VERSION 5.7 ;
  NOWIREEXTENSIONATPIN ON ;
  DIVIDERCHAR "/" ;
  BUSBITCHARS "[]" ;
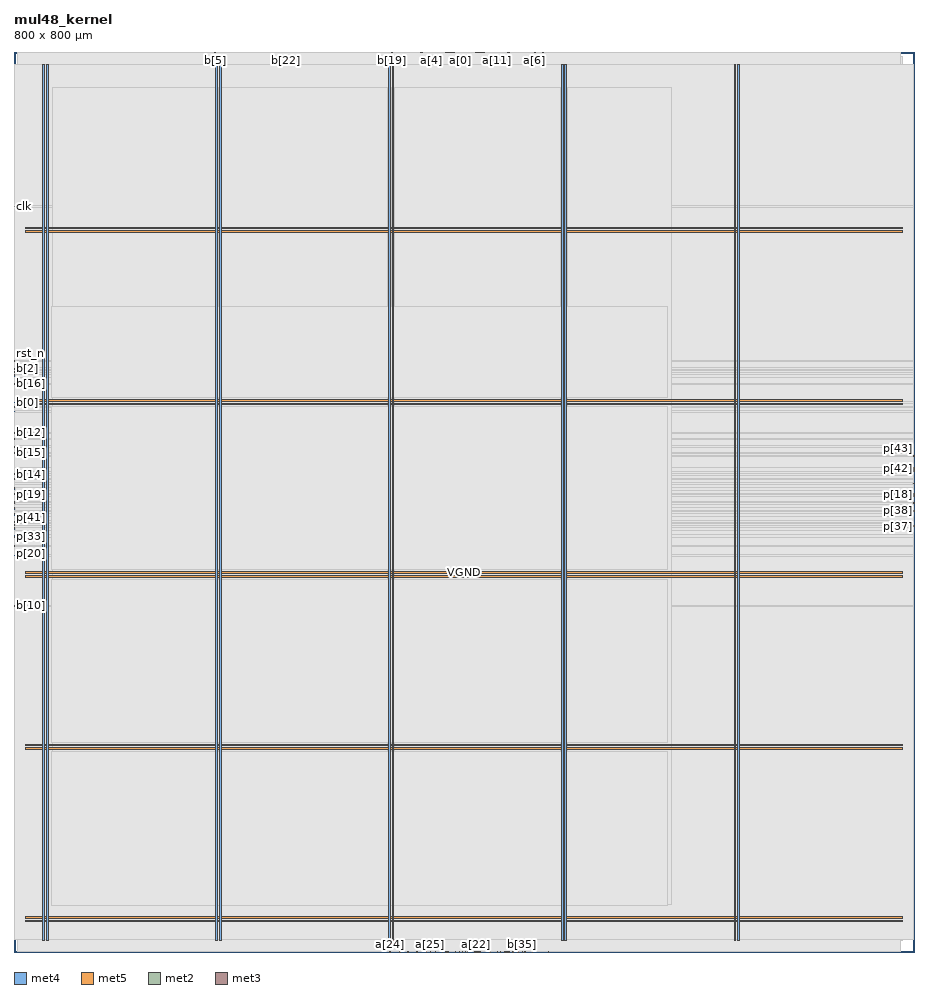
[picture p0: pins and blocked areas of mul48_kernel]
MACRO mul48_kernel
  CLASS BLOCK ;
  FOREIGN mul48_kernel ;
  ORIGIN 0.000 0.000 ;
  SIZE 800.000 BY 800.000 ;
  PIN VGND
    DIRECTION INOUT ;
    USE GROUND ;
    PORT
      LAYER met4 ;
        RECT 28.940 10.640 30.540 789.040 ;
    END
    PORT
      LAYER met4 ;
        RECT 182.540 10.640 184.140 789.040 ;
    END
    PORT
      LAYER met4 ;
        RECT 336.140 10.640 337.740 789.040 ;
    END
    PORT
      LAYER met4 ;
        RECT 489.740 10.640 491.340 789.040 ;
    END
    PORT
      LAYER met4 ;
        RECT 643.340 10.640 644.940 789.040 ;
    END
    PORT
      LAYER met5 ;
        RECT 10.120 30.030 789.820 31.630 ;
    END
    PORT
      LAYER met5 ;
        RECT 10.120 183.210 789.820 184.810 ;
    END
    PORT
      LAYER met5 ;
        RECT 10.120 336.390 789.820 337.990 ;
    END
    PORT
      LAYER met5 ;
        RECT 10.120 489.570 789.820 491.170 ;
    END
    PORT
      LAYER met5 ;
        RECT 10.120 642.750 789.820 644.350 ;
    END
  END VGND
  PIN VPWR
    DIRECTION INOUT ;
    USE POWER ;
    PORT
      LAYER met4 ;
        RECT 25.640 10.640 27.240 789.040 ;
    END
    PORT
      LAYER met4 ;
        RECT 179.240 10.640 180.840 789.040 ;
    END
    PORT
      LAYER met4 ;
        RECT 332.840 10.640 334.440 789.040 ;
    END
    PORT
      LAYER met4 ;
        RECT 486.440 10.640 488.040 789.040 ;
    END
    PORT
      LAYER met4 ;
        RECT 640.040 10.640 641.640 789.040 ;
    END
    PORT
      LAYER met5 ;
        RECT 10.120 26.730 789.820 28.330 ;
    END
    PORT
      LAYER met5 ;
        RECT 10.120 179.910 789.820 181.510 ;
    END
    PORT
      LAYER met5 ;
        RECT 10.120 333.090 789.820 334.690 ;
    END
    PORT
      LAYER met5 ;
        RECT 10.120 486.270 789.820 487.870 ;
    END
    PORT
      LAYER met5 ;
        RECT 10.120 639.450 789.820 641.050 ;
    END
  END VPWR
  PIN a[0]
    DIRECTION INPUT ;
    USE SIGNAL ;
    ANTENNAGATEAREA 0.159000 ;
    PORT
      LAYER met2 ;
        RECT 396.610 799.720 396.890 800.000 ;
    END
  END a[0]
  PIN a[10]
    DIRECTION INPUT ;
    USE SIGNAL ;
    ANTENNAGATEAREA 0.159000 ;
    PORT
      LAYER met2 ;
        RECT 419.610 799.720 419.890 800.000 ;
    END
  END a[10]
  PIN a[11]
    DIRECTION INPUT ;
    USE SIGNAL ;
    ANTENNAGATEAREA 0.159000 ;
    PORT
      LAYER met2 ;
        RECT 428.810 799.720 429.090 800.000 ;
    END
  END a[11]
  PIN a[12]
    DIRECTION INPUT ;
    USE SIGNAL ;
    ANTENNAGATEAREA 0.159000 ;
    PORT
      LAYER met2 ;
        RECT 377.290 799.720 377.570 800.000 ;
    END
  END a[12]
  PIN a[13]
    DIRECTION INPUT ;
    USE SIGNAL ;
    ANTENNAGATEAREA 0.159000 ;
    PORT
      LAYER met2 ;
        RECT 397.530 799.720 397.810 800.000 ;
    END
  END a[13]
  PIN a[14]
    DIRECTION INPUT ;
    USE SIGNAL ;
    ANTENNAGATEAREA 0.159000 ;
    PORT
      LAYER met2 ;
        RECT 439.850 799.720 440.130 800.000 ;
    END
  END a[14]
  PIN a[15]
    DIRECTION INPUT ;
    USE SIGNAL ;
    ANTENNAGATEAREA 0.159000 ;
    PORT
      LAYER met2 ;
        RECT 378.210 799.720 378.490 800.000 ;
    END
  END a[15]
  PIN a[16]
    DIRECTION INPUT ;
    USE SIGNAL ;
    ANTENNAGATEAREA 0.159000 ;
    PORT
      LAYER met2 ;
        RECT 416.850 799.720 417.130 800.000 ;
    END
  END a[16]
  PIN a[17]
    DIRECTION INPUT ;
    USE SIGNAL ;
    ANTENNAGATEAREA 0.159000 ;
    PORT
      LAYER met2 ;
        RECT 380.970 799.720 381.250 800.000 ;
    END
  END a[17]
  PIN a[18]
    DIRECTION INPUT ;
    USE SIGNAL ;
    ANTENNAGATEAREA 0.159000 ;
    PORT
      LAYER met2 ;
        RECT 372.690 799.720 372.970 800.000 ;
    END
  END a[18]
  PIN a[19]
    DIRECTION INPUT ;
    USE SIGNAL ;
    ANTENNAGATEAREA 0.159000 ;
    PORT
      LAYER met2 ;
        RECT 373.610 799.720 373.890 800.000 ;
    END
  END a[19]
  PIN a[1]
    DIRECTION INPUT ;
    USE SIGNAL ;
    ANTENNAGATEAREA 0.159000 ;
    PORT
      LAYER met2 ;
        RECT 417.770 799.720 418.050 800.000 ;
    END
  END a[1]
  PIN a[20]
    DIRECTION INPUT ;
    USE SIGNAL ;
    ANTENNAGATEAREA 0.159000 ;
    PORT
      LAYER met2 ;
        RECT 448.130 0.000 448.410 0.280 ;
    END
  END a[20]
  PIN a[21]
    DIRECTION INPUT ;
    USE SIGNAL ;
    ANTENNAGATEAREA 0.159000 ;
    PORT
      LAYER met2 ;
        RECT 443.530 0.000 443.810 0.280 ;
    END
  END a[21]
  PIN a[22]
    DIRECTION INPUT ;
    USE SIGNAL ;
    ANTENNAGATEAREA 0.159000 ;
    PORT
      LAYER met2 ;
        RECT 410.410 0.000 410.690 0.280 ;
    END
  END a[22]
  PIN a[23]
    DIRECTION INPUT ;
    USE SIGNAL ;
    ANTENNAGATEAREA 0.159000 ;
    PORT
      LAYER met2 ;
        RECT 436.170 0.000 436.450 0.280 ;
    END
  END a[23]
  PIN a[24]
    DIRECTION INPUT ;
    USE SIGNAL ;
    ANTENNAGATEAREA 0.159000 ;
    PORT
      LAYER met2 ;
        RECT 334.050 0.000 334.330 0.280 ;
    END
  END a[24]
  PIN a[25]
    DIRECTION INPUT ;
    USE SIGNAL ;
    ANTENNAGATEAREA 0.159000 ;
    PORT
      LAYER met2 ;
        RECT 369.930 0.000 370.210 0.280 ;
    END
  END a[25]
  PIN a[26]
    DIRECTION INPUT ;
    USE SIGNAL ;
    ANTENNAGATEAREA 0.159000 ;
    PORT
      LAYER met2 ;
        RECT 423.290 0.000 423.570 0.280 ;
    END
  END a[26]
  PIN a[27]
    DIRECTION INPUT ;
    USE SIGNAL ;
    ANTENNAGATEAREA 0.159000 ;
    PORT
      LAYER met2 ;
        RECT 392.010 0.000 392.290 0.280 ;
    END
  END a[27]
  PIN a[28]
    DIRECTION INPUT ;
    USE SIGNAL ;
    ANTENNAGATEAREA 0.159000 ;
    PORT
      LAYER met2 ;
        RECT 349.690 0.000 349.970 0.280 ;
    END
  END a[28]
  PIN a[29]
    DIRECTION INPUT ;
    USE SIGNAL ;
    ANTENNAGATEAREA 0.159000 ;
    PORT
      LAYER met2 ;
        RECT 422.370 0.000 422.650 0.280 ;
    END
  END a[29]
  PIN a[2]
    DIRECTION INPUT ;
    USE SIGNAL ;
    ANTENNAGATEAREA 0.159000 ;
    PORT
      LAYER met2 ;
        RECT 408.570 799.720 408.850 800.000 ;
    END
  END a[2]
  PIN a[30]
    DIRECTION INPUT ;
    USE SIGNAL ;
    ANTENNAGATEAREA 0.159000 ;
    PORT
      LAYER met2 ;
        RECT 403.050 0.000 403.330 0.280 ;
    END
  END a[30]
  PIN a[31]
    DIRECTION INPUT ;
    USE SIGNAL ;
    ANTENNAGATEAREA 0.159000 ;
    PORT
      LAYER met2 ;
        RECT 434.330 799.720 434.610 800.000 ;
    END
  END a[31]
  PIN a[3]
    DIRECTION INPUT ;
    USE SIGNAL ;
    ANTENNAGATEAREA 0.159000 ;
    PORT
      LAYER met2 ;
        RECT 435.250 799.720 435.530 800.000 ;
    END
  END a[3]
  PIN a[4]
    DIRECTION INPUT ;
    USE SIGNAL ;
    ANTENNAGATEAREA 0.159000 ;
    PORT
      LAYER met2 ;
        RECT 370.850 799.720 371.130 800.000 ;
    END
  END a[4]
  PIN a[5]
    DIRECTION INPUT ;
    USE SIGNAL ;
    ANTENNAGATEAREA 0.159000 ;
    PORT
      LAYER met2 ;
        RECT 375.450 799.720 375.730 800.000 ;
    END
  END a[5]
  PIN a[6]
    DIRECTION INPUT ;
    USE SIGNAL ;
    ANTENNAGATEAREA 0.159000 ;
    PORT
      LAYER met2 ;
        RECT 462.850 799.720 463.130 800.000 ;
    END
  END a[6]
  PIN a[7]
    DIRECTION INPUT ;
    USE SIGNAL ;
    ANTENNAGATEAREA 0.159000 ;
    PORT
      LAYER met2 ;
        RECT 382.810 799.720 383.090 800.000 ;
    END
  END a[7]
  PIN a[8]
    DIRECTION INPUT ;
    USE SIGNAL ;
    ANTENNAGATEAREA 0.159000 ;
    PORT
      LAYER met2 ;
        RECT 411.330 799.720 411.610 800.000 ;
    END
  END a[8]
  PIN a[9]
    DIRECTION INPUT ;
    USE SIGNAL ;
    ANTENNAGATEAREA 0.159000 ;
    PORT
      LAYER met2 ;
        RECT 451.810 799.720 452.090 800.000 ;
    END
  END a[9]
  PIN b[0]
    DIRECTION INPUT ;
    USE SIGNAL ;
    ANTENNAGATEAREA 0.159000 ;
    PORT
      LAYER met3 ;
        RECT 0.000 488.280 0.600 488.880 ;
    END
  END b[0]
  PIN b[10]
    DIRECTION INPUT ;
    USE SIGNAL ;
    ANTENNAGATEAREA 0.159000 ;
    PORT
      LAYER met3 ;
        RECT 0.000 307.400 0.600 308.000 ;
    END
  END b[10]
  PIN b[11]
    DIRECTION INPUT ;
    USE SIGNAL ;
    ANTENNAGATEAREA 0.159000 ;
    PORT
      LAYER met3 ;
        RECT 0.000 412.120 0.600 412.720 ;
    END
  END b[11]
  PIN b[12]
    DIRECTION INPUT ;
    USE SIGNAL ;
    ANTENNAGATEAREA 0.159000 ;
    PORT
      LAYER met3 ;
        RECT 0.000 461.080 0.600 461.680 ;
    END
  END b[12]
  PIN b[13]
    DIRECTION INPUT ;
    USE SIGNAL ;
    ANTENNAGATEAREA 0.159000 ;
    PORT
      LAYER met3 ;
        RECT 0.000 375.400 0.600 376.000 ;
    END
  END b[13]
  PIN b[14]
    DIRECTION INPUT ;
    USE SIGNAL ;
    ANTENNAGATEAREA 0.159000 ;
    PORT
      LAYER met3 ;
        RECT 0.000 424.360 0.600 424.960 ;
    END
  END b[14]
  PIN b[15]
    DIRECTION INPUT ;
    USE SIGNAL ;
    ANTENNAGATEAREA 0.159000 ;
    PORT
      LAYER met3 ;
        RECT 0.000 443.400 0.600 444.000 ;
    END
  END b[15]
  PIN b[16]
    DIRECTION INPUT ;
    USE SIGNAL ;
    ANTENNAGATEAREA 0.159000 ;
    PORT
      LAYER met3 ;
        RECT 0.000 504.600 0.600 505.200 ;
    END
  END b[16]
  PIN b[17]
    DIRECTION INPUT ;
    USE SIGNAL ;
    ANTENNAGATEAREA 0.159000 ;
    PORT
      LAYER met3 ;
        RECT 0.000 511.400 0.600 512.000 ;
    END
  END b[17]
  PIN b[18]
    DIRECTION INPUT ;
    USE SIGNAL ;
    ANTENNAGATEAREA 0.159000 ;
    PORT
      LAYER met3 ;
        RECT 0.000 480.120 0.600 480.720 ;
    END
  END b[18]
  PIN b[19]
    DIRECTION INPUT ;
    USE SIGNAL ;
    ANTENNAGATEAREA 0.159000 ;
    PORT
      LAYER met2 ;
        RECT 335.890 799.720 336.170 800.000 ;
    END
  END b[19]
  PIN b[1]
    DIRECTION INPUT ;
    USE SIGNAL ;
    ANTENNAGATEAREA 0.159000 ;
    PORT
      LAYER met3 ;
        RECT 0.000 515.480 0.600 516.080 ;
    END
  END b[1]
  PIN b[20]
    DIRECTION INPUT ;
    USE SIGNAL ;
    ANTENNAGATEAREA 0.159000 ;
    PORT
      LAYER met2 ;
        RECT 347.850 799.720 348.130 800.000 ;
    END
  END b[20]
  PIN b[21]
    DIRECTION INPUT ;
    USE SIGNAL ;
    ANTENNAGATEAREA 0.159000 ;
    PORT
      LAYER met2 ;
        RECT 395.690 799.720 395.970 800.000 ;
    END
  END b[21]
  PIN b[22]
    DIRECTION INPUT ;
    USE SIGNAL ;
    ANTENNAGATEAREA 0.159000 ;
    PORT
      LAYER met2 ;
        RECT 242.050 799.720 242.330 800.000 ;
    END
  END b[22]
  PIN b[23]
    DIRECTION INPUT ;
    USE SIGNAL ;
    ANTENNAGATEAREA 0.159000 ;
    PORT
      LAYER met2 ;
        RECT 326.690 799.720 326.970 800.000 ;
    END
  END b[23]
  PIN b[24]
    DIRECTION INPUT ;
    USE SIGNAL ;
    ANTENNAGATEAREA 0.159000 ;
    PORT
      LAYER met2 ;
        RECT 427.890 799.720 428.170 800.000 ;
    END
  END b[24]
  PIN b[25]
    DIRECTION INPUT ;
    USE SIGNAL ;
    ANTENNAGATEAREA 0.159000 ;
    PORT
      LAYER met2 ;
        RECT 362.570 799.720 362.850 800.000 ;
    END
  END b[25]
  PIN b[26]
    DIRECTION INPUT ;
    USE SIGNAL ;
    ANTENNAGATEAREA 0.159000 ;
    PORT
      LAYER met2 ;
        RECT 449.970 799.720 450.250 800.000 ;
    END
  END b[26]
  PIN b[27]
    DIRECTION INPUT ;
    USE SIGNAL ;
    ANTENNAGATEAREA 0.159000 ;
    PORT
      LAYER met2 ;
        RECT 381.890 799.720 382.170 800.000 ;
    END
  END b[27]
  PIN b[28]
    DIRECTION INPUT ;
    USE SIGNAL ;
    ANTENNAGATEAREA 0.159000 ;
    PORT
      LAYER met2 ;
        RECT 361.650 799.720 361.930 800.000 ;
    END
  END b[28]
  PIN b[29]
    DIRECTION INPUT ;
    USE SIGNAL ;
    ANTENNAGATEAREA 0.159000 ;
    PORT
      LAYER met2 ;
        RECT 356.130 799.720 356.410 800.000 ;
    END
  END b[29]
  PIN b[2]
    DIRECTION INPUT ;
    USE SIGNAL ;
    ANTENNAGATEAREA 0.159000 ;
    PORT
      LAYER met3 ;
        RECT 0.000 518.200 0.600 518.800 ;
    END
  END b[2]
  PIN b[30]
    DIRECTION INPUT ;
    USE SIGNAL ;
    ANTENNAGATEAREA 0.159000 ;
    PORT
      LAYER met2 ;
        RECT 409.490 799.720 409.770 800.000 ;
    END
  END b[30]
  PIN b[31]
    DIRECTION INPUT ;
    USE SIGNAL ;
    ANTENNAGATEAREA 0.159000 ;
    PORT
      LAYER met2 ;
        RECT 383.730 799.720 384.010 800.000 ;
    END
  END b[31]
  PIN b[32]
    DIRECTION INPUT ;
    USE SIGNAL ;
    ANTENNAGATEAREA 0.159000 ;
    PORT
      LAYER met2 ;
        RECT 431.570 799.720 431.850 800.000 ;
    END
  END b[32]
  PIN b[33]
    DIRECTION INPUT ;
    USE SIGNAL ;
    ANTENNAGATEAREA 0.159000 ;
    PORT
      LAYER met2 ;
        RECT 407.650 799.720 407.930 800.000 ;
    END
  END b[33]
  PIN b[34]
    DIRECTION INPUT ;
    USE SIGNAL ;
    ANTENNAGATEAREA 0.159000 ;
    PORT
      LAYER met2 ;
        RECT 403.050 799.720 403.330 800.000 ;
    END
  END b[34]
  PIN b[35]
    DIRECTION INPUT ;
    USE SIGNAL ;
    ANTENNAGATEAREA 0.159000 ;
    PORT
      LAYER met2 ;
        RECT 451.810 0.000 452.090 0.280 ;
    END
  END b[35]
  PIN b[36]
    DIRECTION INPUT ;
    USE SIGNAL ;
    ANTENNAGATEAREA 0.159000 ;
    PORT
      LAYER met2 ;
        RECT 461.010 0.000 461.290 0.280 ;
    END
  END b[36]
  PIN b[37]
    DIRECTION INPUT ;
    USE SIGNAL ;
    ANTENNAGATEAREA 0.159000 ;
    PORT
      LAYER met2 ;
        RECT 380.970 0.000 381.250 0.280 ;
    END
  END b[37]
  PIN b[38]
    DIRECTION INPUT ;
    USE SIGNAL ;
    ANTENNAGATEAREA 0.159000 ;
    PORT
      LAYER met2 ;
        RECT 343.250 0.000 343.530 0.280 ;
    END
  END b[38]
  PIN b[39]
    DIRECTION INPUT ;
    USE SIGNAL ;
    ANTENNAGATEAREA 0.159000 ;
    PORT
      LAYER met2 ;
        RECT 412.250 0.000 412.530 0.280 ;
    END
  END b[39]
  PIN b[3]
    DIRECTION INPUT ;
    USE SIGNAL ;
    ANTENNAGATEAREA 0.159000 ;
    PORT
      LAYER met3 ;
        RECT 0.000 455.640 0.600 456.240 ;
    END
  END b[3]
  PIN b[40]
    DIRECTION INPUT ;
    USE SIGNAL ;
    ANTENNAGATEAREA 0.159000 ;
    PORT
      LAYER met2 ;
        RECT 454.570 0.000 454.850 0.280 ;
    END
  END b[40]
  PIN b[41]
    DIRECTION INPUT ;
    USE SIGNAL ;
    ANTENNAGATEAREA 0.159000 ;
    PORT
      LAYER met2 ;
        RECT 395.690 0.000 395.970 0.280 ;
    END
  END b[41]
  PIN b[42]
    DIRECTION INPUT ;
    USE SIGNAL ;
    ANTENNAGATEAREA 0.159000 ;
    PORT
      LAYER met2 ;
        RECT 366.250 0.000 366.530 0.280 ;
    END
  END b[42]
  PIN b[43]
    DIRECTION INPUT ;
    USE SIGNAL ;
    ANTENNAGATEAREA 0.159000 ;
    PORT
      LAYER met2 ;
        RECT 447.210 0.000 447.490 0.280 ;
    END
  END b[43]
  PIN b[44]
    DIRECTION INPUT ;
    USE SIGNAL ;
    ANTENNAGATEAREA 0.159000 ;
    PORT
      LAYER met2 ;
        RECT 384.650 0.000 384.930 0.280 ;
    END
  END b[44]
  PIN b[45]
    DIRECTION INPUT ;
    USE SIGNAL ;
    ANTENNAGATEAREA 0.159000 ;
    PORT
      LAYER met2 ;
        RECT 350.610 0.000 350.890 0.280 ;
    END
  END b[45]
  PIN b[46]
    DIRECTION INPUT ;
    USE SIGNAL ;
    ANTENNAGATEAREA 0.159000 ;
    PORT
      LAYER met2 ;
        RECT 429.730 0.000 430.010 0.280 ;
    END
  END b[46]
  PIN b[47]
    DIRECTION INPUT ;
    USE SIGNAL ;
    ANTENNAGATEAREA 0.159000 ;
    PORT
      LAYER met2 ;
        RECT 342.330 0.000 342.610 0.280 ;
    END
  END b[47]
  PIN b[48]
    DIRECTION INPUT ;
    USE SIGNAL ;
    ANTENNAGATEAREA 0.159000 ;
    PORT
      LAYER met2 ;
        RECT 383.730 0.000 384.010 0.280 ;
    END
  END b[48]
  PIN b[49]
    DIRECTION INPUT ;
    USE SIGNAL ;
    ANTENNAGATEAREA 0.159000 ;
    PORT
      LAYER met2 ;
        RECT 401.210 0.000 401.490 0.280 ;
    END
  END b[49]
  PIN b[4]
    DIRECTION INPUT ;
    USE SIGNAL ;
    ANTENNAGATEAREA 0.159000 ;
    PORT
      LAYER met3 ;
        RECT 0.000 484.200 0.600 484.800 ;
    END
  END b[4]
  PIN b[50]
    DIRECTION INPUT ;
    USE SIGNAL ;
    ANTENNAGATEAREA 0.159000 ;
    PORT
      LAYER met2 ;
        RECT 357.970 0.000 358.250 0.280 ;
    END
  END b[50]
  PIN b[51]
    DIRECTION INPUT ;
    USE SIGNAL ;
    ANTENNAGATEAREA 0.159000 ;
    PORT
      LAYER met2 ;
        RECT 374.530 0.000 374.810 0.280 ;
    END
  END b[51]
  PIN b[52]
    DIRECTION INPUT ;
    USE SIGNAL ;
    ANTENNAGATEAREA 0.159000 ;
    PORT
      LAYER met2 ;
        RECT 432.490 0.000 432.770 0.280 ;
    END
  END b[52]
  PIN b[53]
    DIRECTION INPUT ;
    USE SIGNAL ;
    ANTENNAGATEAREA 0.159000 ;
    PORT
      LAYER met2 ;
        RECT 438.010 0.000 438.290 0.280 ;
    END
  END b[53]
  PIN b[54]
    DIRECTION INPUT ;
    USE SIGNAL ;
    ANTENNAGATEAREA 0.159000 ;
    PORT
      LAYER met2 ;
        RECT 453.650 0.000 453.930 0.280 ;
    END
  END b[54]
  PIN b[55]
    DIRECTION INPUT ;
    USE SIGNAL ;
    ANTENNAGATEAREA 0.159000 ;
    PORT
      LAYER met2 ;
        RECT 439.850 0.000 440.130 0.280 ;
    END
  END b[55]
  PIN b[56]
    DIRECTION INPUT ;
    USE SIGNAL ;
    ANTENNAGATEAREA 0.159000 ;
    PORT
      LAYER met2 ;
        RECT 474.810 0.000 475.090 0.280 ;
    END
  END b[56]
  PIN b[57]
    DIRECTION INPUT ;
    USE SIGNAL ;
    ANTENNAGATEAREA 0.159000 ;
    PORT
      LAYER met2 ;
        RECT 449.050 799.720 449.330 800.000 ;
    END
  END b[57]
  PIN b[58]
    DIRECTION INPUT ;
    USE SIGNAL ;
    ANTENNAGATEAREA 0.159000 ;
    PORT
      LAYER met2 ;
        RECT 456.410 799.720 456.690 800.000 ;
    END
  END b[58]
  PIN b[59]
    DIRECTION INPUT ;
    USE SIGNAL ;
    ANTENNAGATEAREA 0.159000 ;
    PORT
      LAYER met2 ;
        RECT 461.010 799.720 461.290 800.000 ;
    END
  END b[59]
  PIN b[5]
    DIRECTION INPUT ;
    USE SIGNAL ;
    ANTENNAGATEAREA 0.159000 ;
    PORT
      LAYER met2 ;
        RECT 178.570 799.720 178.850 800.000 ;
    END
  END b[5]
  PIN b[60]
    DIRECTION INPUT ;
    USE SIGNAL ;
    ANTENNAGATEAREA 0.159000 ;
    PORT
      LAYER met2 ;
        RECT 471.130 799.720 471.410 800.000 ;
    END
  END b[60]
  PIN b[61]
    DIRECTION INPUT ;
    USE SIGNAL ;
    ANTENNAGATEAREA 0.159000 ;
    PORT
      LAYER met2 ;
        RECT 470.210 799.720 470.490 800.000 ;
    END
  END b[61]
  PIN b[62]
    DIRECTION INPUT ;
    USE SIGNAL ;
    ANTENNAGATEAREA 0.159000 ;
    PORT
      LAYER met2 ;
        RECT 479.410 799.720 479.690 800.000 ;
    END
  END b[62]
  PIN b[63]
    DIRECTION INPUT ;
    USE SIGNAL ;
    ANTENNAGATEAREA 0.159000 ;
    PORT
      LAYER met2 ;
        RECT 480.330 799.720 480.610 800.000 ;
    END
  END b[63]
  PIN b[6]
    DIRECTION INPUT ;
    USE SIGNAL ;
    ANTENNAGATEAREA 0.159000 ;
    PORT
      LAYER met3 ;
        RECT 0.000 512.760 0.600 513.360 ;
    END
  END b[6]
  PIN b[7]
    DIRECTION INPUT ;
    USE SIGNAL ;
    ANTENNAGATEAREA 0.159000 ;
    PORT
      LAYER met3 ;
        RECT 0.000 448.840 0.600 449.440 ;
    END
  END b[7]
  PIN b[8]
    DIRECTION INPUT ;
    USE SIGNAL ;
    ANTENNAGATEAREA 0.159000 ;
    PORT
      LAYER met3 ;
        RECT 0.000 399.880 0.600 400.480 ;
    END
  END b[8]
  PIN b[9]
    DIRECTION INPUT ;
    USE SIGNAL ;
    ANTENNAGATEAREA 0.159000 ;
    PORT
      LAYER met3 ;
        RECT 0.000 389.000 0.600 389.600 ;
    END
  END b[9]
  PIN clk
    DIRECTION INPUT ;
    USE SIGNAL ;
    ANTENNAGATEAREA 0.852000 ;
    PORT
      LAYER met3 ;
        RECT 0.000 662.360 0.600 662.960 ;
    END
  END clk
  PIN p[0]
    DIRECTION OUTPUT ;
    USE SIGNAL ;
    ANTENNADIFFAREA 0.445500 ;
    PORT
      LAYER met2 ;
        RECT 369.930 799.720 370.210 800.000 ;
    END
  END p[0]
  PIN p[10]
    DIRECTION OUTPUT ;
    USE SIGNAL ;
    ANTENNADIFFAREA 0.445500 ;
    PORT
      LAYER met2 ;
        RECT 387.410 799.720 387.690 800.000 ;
    END
  END p[10]
  PIN p[11]
    DIRECTION OUTPUT ;
    USE SIGNAL ;
    ANTENNADIFFAREA 0.445500 ;
    PORT
      LAYER met2 ;
        RECT 389.250 799.720 389.530 800.000 ;
    END
  END p[11]
  PIN p[12]
    DIRECTION OUTPUT ;
    USE SIGNAL ;
    ANTENNADIFFAREA 0.445500 ;
    PORT
      LAYER met2 ;
        RECT 398.450 799.720 398.730 800.000 ;
    END
  END p[12]
  PIN p[13]
    DIRECTION OUTPUT ;
    USE SIGNAL ;
    ANTENNADIFFAREA 0.445500 ;
    PORT
      LAYER met2 ;
        RECT 391.090 799.720 391.370 800.000 ;
    END
  END p[13]
  PIN p[14]
    DIRECTION OUTPUT ;
    USE SIGNAL ;
    ANTENNADIFFAREA 0.445500 ;
    PORT
      LAYER met2 ;
        RECT 399.370 799.720 399.650 800.000 ;
    END
  END p[14]
  PIN p[15]
    DIRECTION OUTPUT ;
    USE SIGNAL ;
    ANTENNADIFFAREA 0.445500 ;
    PORT
      LAYER met2 ;
        RECT 384.650 799.720 384.930 800.000 ;
    END
  END p[15]
  PIN p[16]
    DIRECTION OUTPUT ;
    USE SIGNAL ;
    ANTENNADIFFAREA 0.445500 ;
    PORT
      LAYER met3 ;
        RECT 0.000 398.520 0.600 399.120 ;
    END
  END p[16]
  PIN p[17]
    DIRECTION OUTPUT ;
    USE SIGNAL ;
    ANTENNADIFFAREA 0.445500 ;
    PORT
      LAYER met3 ;
        RECT 0.000 394.440 0.600 395.040 ;
    END
  END p[17]
  PIN p[18]
    DIRECTION OUTPUT ;
    USE SIGNAL ;
    ANTENNADIFFAREA 0.445500 ;
    PORT
      LAYER met3 ;
        RECT 799.400 406.680 800.000 407.280 ;
    END
  END p[18]
  PIN p[19]
    DIRECTION OUTPUT ;
    USE SIGNAL ;
    ANTENNADIFFAREA 0.445500 ;
    PORT
      LAYER met3 ;
        RECT 0.000 406.680 0.600 407.280 ;
    END
  END p[19]
  PIN p[1]
    DIRECTION OUTPUT ;
    USE SIGNAL ;
    ANTENNADIFFAREA 0.445500 ;
    PORT
      LAYER met2 ;
        RECT 388.330 799.720 388.610 800.000 ;
    END
  END p[1]
  PIN p[20]
    DIRECTION OUTPUT ;
    USE SIGNAL ;
    ANTENNADIFFAREA 0.445500 ;
    PORT
      LAYER met3 ;
        RECT 0.000 360.440 0.600 361.040 ;
    END
  END p[20]
  PIN p[21]
    DIRECTION OUTPUT ;
    USE SIGNAL ;
    ANTENNADIFFAREA 0.445500 ;
    PORT
      LAYER met3 ;
        RECT 0.000 369.960 0.600 370.560 ;
    END
  END p[21]
  PIN p[22]
    DIRECTION OUTPUT ;
    USE SIGNAL ;
    ANTENNADIFFAREA 0.445500 ;
    PORT
      LAYER met3 ;
        RECT 0.000 382.200 0.600 382.800 ;
    END
  END p[22]
  PIN p[23]
    DIRECTION OUTPUT ;
    USE SIGNAL ;
    ANTENNADIFFAREA 0.445500 ;
    PORT
      LAYER met3 ;
        RECT 0.000 387.640 0.600 388.240 ;
    END
  END p[23]
  PIN p[24]
    DIRECTION OUTPUT ;
    USE SIGNAL ;
    ANTENNADIFFAREA 0.445500 ;
    PORT
      LAYER met3 ;
        RECT 0.000 352.280 0.600 352.880 ;
    END
  END p[24]
  PIN p[25]
    DIRECTION OUTPUT ;
    USE SIGNAL ;
    ANTENNADIFFAREA 0.445500 ;
    PORT
      LAYER met3 ;
        RECT 0.000 410.760 0.600 411.360 ;
    END
  END p[25]
  PIN p[26]
    DIRECTION OUTPUT ;
    USE SIGNAL ;
    ANTENNADIFFAREA 0.445500 ;
    PORT
      LAYER met3 ;
        RECT 0.000 420.280 0.600 420.880 ;
    END
  END p[26]
  PIN p[27]
    DIRECTION OUTPUT ;
    USE SIGNAL ;
    ANTENNADIFFAREA 0.445500 ;
    PORT
      LAYER met2 ;
        RECT 385.570 0.000 385.850 0.280 ;
    END
  END p[27]
  PIN p[28]
    DIRECTION OUTPUT ;
    USE SIGNAL ;
    ANTENNADIFFAREA 0.445500 ;
    PORT
      LAYER met3 ;
        RECT 0.000 376.760 0.600 377.360 ;
    END
  END p[28]
  PIN p[29]
    DIRECTION OUTPUT ;
    USE SIGNAL ;
    ANTENNADIFFAREA 0.445500 ;
    PORT
      LAYER met3 ;
        RECT 799.400 416.200 800.000 416.800 ;
    END
  END p[29]
  PIN p[2]
    DIRECTION OUTPUT ;
    USE SIGNAL ;
    ANTENNADIFFAREA 0.445500 ;
    PORT
      LAYER met2 ;
        RECT 380.050 799.720 380.330 800.000 ;
    END
  END p[2]
  PIN p[30]
    DIRECTION OUTPUT ;
    USE SIGNAL ;
    ANTENNADIFFAREA 0.445500 ;
    PORT
      LAYER met2 ;
        RECT 410.410 799.720 410.690 800.000 ;
    END
  END p[30]
  PIN p[31]
    DIRECTION OUTPUT ;
    USE SIGNAL ;
    ANTENNADIFFAREA 0.445500 ;
    PORT
      LAYER met3 ;
        RECT 0.000 393.080 0.600 393.680 ;
    END
  END p[31]
  PIN p[32]
    DIRECTION OUTPUT ;
    USE SIGNAL ;
    ANTENNADIFFAREA 0.445500 ;
    PORT
      LAYER met2 ;
        RECT 398.450 0.000 398.730 0.280 ;
    END
  END p[32]
  PIN p[33]
    DIRECTION OUTPUT ;
    USE SIGNAL ;
    ANTENNADIFFAREA 0.445500 ;
    PORT
      LAYER met3 ;
        RECT 0.000 368.600 0.600 369.200 ;
    END
  END p[33]
  PIN p[34]
    DIRECTION OUTPUT ;
    USE SIGNAL ;
    ANTENNADIFFAREA 0.445500 ;
    PORT
      LAYER met3 ;
        RECT 799.400 398.520 800.000 399.120 ;
    END
  END p[34]
  PIN p[35]
    DIRECTION OUTPUT ;
    USE SIGNAL ;
    ANTENNADIFFAREA 0.445500 ;
    PORT
      LAYER met3 ;
        RECT 799.400 427.080 800.000 427.680 ;
    END
  END p[35]
  PIN p[36]
    DIRECTION OUTPUT ;
    USE SIGNAL ;
    ANTENNADIFFAREA 0.445500 ;
    PORT
      LAYER met2 ;
        RECT 413.170 0.000 413.450 0.280 ;
    END
  END p[36]
  PIN p[37]
    DIRECTION OUTPUT ;
    USE SIGNAL ;
    ANTENNADIFFAREA 0.445500 ;
    PORT
      LAYER met3 ;
        RECT 799.400 378.120 800.000 378.720 ;
    END
  END p[37]
  PIN p[38]
    DIRECTION OUTPUT ;
    USE SIGNAL ;
    ANTENNADIFFAREA 0.445500 ;
    PORT
      LAYER met3 ;
        RECT 799.400 391.720 800.000 392.320 ;
    END
  END p[38]
  PIN p[39]
    DIRECTION OUTPUT ;
    USE SIGNAL ;
    ANTENNADIFFAREA 0.445500 ;
    PORT
      LAYER met2 ;
        RECT 409.490 0.000 409.770 0.280 ;
    END
  END p[39]
  PIN p[3]
    DIRECTION OUTPUT ;
    USE SIGNAL ;
    ANTENNADIFFAREA 0.445500 ;
    PORT
      LAYER met2 ;
        RECT 385.570 799.720 385.850 800.000 ;
    END
  END p[3]
  PIN p[40]
    DIRECTION OUTPUT ;
    USE SIGNAL ;
    ANTENNADIFFAREA 0.445500 ;
    PORT
      LAYER met2 ;
        RECT 421.450 799.720 421.730 800.000 ;
    END
  END p[40]
  PIN p[41]
    DIRECTION OUTPUT ;
    USE SIGNAL ;
    ANTENNADIFFAREA 0.445500 ;
    PORT
      LAYER met3 ;
        RECT 0.000 379.480 0.600 380.080 ;
    END
  END p[41]
  PIN p[42]
    DIRECTION OUTPUT ;
    USE SIGNAL ;
    ANTENNADIFFAREA 0.445500 ;
    PORT
      LAYER met3 ;
        RECT 799.400 429.800 800.000 430.400 ;
    END
  END p[42]
  PIN p[43]
    DIRECTION OUTPUT ;
    USE SIGNAL ;
    ANTENNADIFFAREA 0.445500 ;
    PORT
      LAYER met3 ;
        RECT 799.400 440.680 800.000 441.280 ;
    END
  END p[43]
  PIN p[44]
    DIRECTION OUTPUT ;
    USE SIGNAL ;
    ANTENNADIFFAREA 0.445500 ;
    PORT
      LAYER met2 ;
        RECT 406.730 799.720 407.010 800.000 ;
    END
  END p[44]
  PIN p[45]
    DIRECTION OUTPUT ;
    USE SIGNAL ;
    ANTENNADIFFAREA 0.445500 ;
    PORT
      LAYER met3 ;
        RECT 799.400 428.440 800.000 429.040 ;
    END
  END p[45]
  PIN p[46]
    DIRECTION OUTPUT ;
    USE SIGNAL ;
    ANTENNADIFFAREA 0.445500 ;
    PORT
      LAYER met2 ;
        RECT 430.650 799.720 430.930 800.000 ;
    END
  END p[46]
  PIN p[47]
    DIRECTION OUTPUT ;
    USE SIGNAL ;
    ANTENNADIFFAREA 0.445500 ;
    PORT
      LAYER met2 ;
        RECT 400.290 799.720 400.570 800.000 ;
    END
  END p[47]
  PIN p[48]
    DIRECTION OUTPUT ;
    USE SIGNAL ;
    ANTENNADIFFAREA 0.445500 ;
    PORT
      LAYER met2 ;
        RECT 425.130 799.720 425.410 800.000 ;
    END
  END p[48]
  PIN p[49]
    DIRECTION OUTPUT ;
    USE SIGNAL ;
    ANTENNADIFFAREA 0.445500 ;
    PORT
      LAYER met3 ;
        RECT 799.400 405.320 800.000 405.920 ;
    END
  END p[49]
  PIN p[4]
    DIRECTION OUTPUT ;
    USE SIGNAL ;
    ANTENNADIFFAREA 0.445500 ;
    PORT
      LAYER met2 ;
        RECT 392.930 799.720 393.210 800.000 ;
    END
  END p[4]
  PIN p[50]
    DIRECTION OUTPUT ;
    USE SIGNAL ;
    ANTENNADIFFAREA 0.445500 ;
    PORT
      LAYER met2 ;
        RECT 413.170 799.720 413.450 800.000 ;
    END
  END p[50]
  PIN p[51]
    DIRECTION OUTPUT ;
    USE SIGNAL ;
    ANTENNADIFFAREA 0.445500 ;
    PORT
      LAYER met2 ;
        RECT 403.970 799.720 404.250 800.000 ;
    END
  END p[51]
  PIN p[52]
    DIRECTION OUTPUT ;
    USE SIGNAL ;
    ANTENNADIFFAREA 0.445500 ;
    PORT
      LAYER met2 ;
        RECT 390.170 799.720 390.450 800.000 ;
    END
  END p[52]
  PIN p[53]
    DIRECTION OUTPUT ;
    USE SIGNAL ;
    ANTENNADIFFAREA 0.445500 ;
    PORT
      LAYER met2 ;
        RECT 420.530 799.720 420.810 800.000 ;
    END
  END p[53]
  PIN p[54]
    DIRECTION OUTPUT ;
    USE SIGNAL ;
    ANTENNADIFFAREA 0.445500 ;
    PORT
      LAYER met2 ;
        RECT 438.930 799.720 439.210 800.000 ;
    END
  END p[54]
  PIN p[55]
    DIRECTION OUTPUT ;
    USE SIGNAL ;
    ANTENNADIFFAREA 0.445500 ;
    PORT
      LAYER met2 ;
        RECT 415.930 799.720 416.210 800.000 ;
    END
  END p[55]
  PIN p[56]
    DIRECTION OUTPUT ;
    USE SIGNAL ;
    ANTENNADIFFAREA 0.445500 ;
    PORT
      LAYER met2 ;
        RECT 415.010 799.720 415.290 800.000 ;
    END
  END p[56]
  PIN p[57]
    DIRECTION OUTPUT ;
    USE SIGNAL ;
    ANTENNADIFFAREA 0.445500 ;
    PORT
      LAYER met2 ;
        RECT 401.210 799.720 401.490 800.000 ;
    END
  END p[57]
  PIN p[58]
    DIRECTION OUTPUT ;
    USE SIGNAL ;
    ANTENNADIFFAREA 0.445500 ;
    PORT
      LAYER met2 ;
        RECT 426.970 799.720 427.250 800.000 ;
    END
  END p[58]
  PIN p[59]
    DIRECTION OUTPUT ;
    USE SIGNAL ;
    ANTENNADIFFAREA 0.445500 ;
    PORT
      LAYER met2 ;
        RECT 402.130 799.720 402.410 800.000 ;
    END
  END p[59]
  PIN p[5]
    DIRECTION OUTPUT ;
    USE SIGNAL ;
    ANTENNADIFFAREA 0.445500 ;
    PORT
      LAYER met2 ;
        RECT 404.890 799.720 405.170 800.000 ;
    END
  END p[5]
  PIN p[60]
    DIRECTION OUTPUT ;
    USE SIGNAL ;
    ANTENNADIFFAREA 0.445500 ;
    PORT
      LAYER met2 ;
        RECT 414.090 799.720 414.370 800.000 ;
    END
  END p[60]
  PIN p[61]
    DIRECTION OUTPUT ;
    USE SIGNAL ;
    ANTENNADIFFAREA 0.445500 ;
    PORT
      LAYER met2 ;
        RECT 405.810 799.720 406.090 800.000 ;
    END
  END p[61]
  PIN p[62]
    DIRECTION OUTPUT ;
    USE SIGNAL ;
    ANTENNADIFFAREA 0.445500 ;
    PORT
      LAYER met2 ;
        RECT 412.250 799.720 412.530 800.000 ;
    END
  END p[62]
  PIN p[63]
    DIRECTION OUTPUT ;
    USE SIGNAL ;
    ANTENNADIFFAREA 0.445500 ;
    PORT
      LAYER met2 ;
        RECT 393.850 799.720 394.130 800.000 ;
    END
  END p[63]
  PIN p[6]
    DIRECTION OUTPUT ;
    USE SIGNAL ;
    ANTENNADIFFAREA 0.445500 ;
    PORT
      LAYER met2 ;
        RECT 394.770 799.720 395.050 800.000 ;
    END
  END p[6]
  PIN p[7]
    DIRECTION OUTPUT ;
    USE SIGNAL ;
    ANTENNADIFFAREA 0.445500 ;
    PORT
      LAYER met2 ;
        RECT 379.130 799.720 379.410 800.000 ;
    END
  END p[7]
  PIN p[8]
    DIRECTION OUTPUT ;
    USE SIGNAL ;
    ANTENNADIFFAREA 0.445500 ;
    PORT
      LAYER met2 ;
        RECT 386.490 799.720 386.770 800.000 ;
    END
  END p[8]
  PIN p[9]
    DIRECTION OUTPUT ;
    USE SIGNAL ;
    ANTENNADIFFAREA 0.445500 ;
    PORT
      LAYER met2 ;
        RECT 392.010 799.720 392.290 800.000 ;
    END
  END p[9]
  PIN ready
    DIRECTION OUTPUT ;
    USE SIGNAL ;
    ANTENNADIFFAREA 0.445500 ;
    PORT
      LAYER met2 ;
        RECT 433.410 799.720 433.690 800.000 ;
    END
  END ready
  PIN rst_n
    DIRECTION INPUT ;
    USE SIGNAL ;
    ANTENNAGATEAREA 0.159000 ;
    PORT
      LAYER met3 ;
        RECT 0.000 525.000 0.600 525.600 ;
    END
  END rst_n
  PIN sat
    DIRECTION OUTPUT ;
    USE SIGNAL ;
    ANTENNADIFFAREA 0.445500 ;
    PORT
      LAYER met2 ;
        RECT 414.090 0.000 414.370 0.280 ;
    END
  END sat
  PIN valid
    DIRECTION INPUT ;
    USE SIGNAL ;
    ANTENNAGATEAREA 0.159000 ;
    PORT
      LAYER met2 ;
        RECT 418.690 799.720 418.970 800.000 ;
    END
  END valid
  OBS
      LAYER nwell ;
        RECT 9.930 10.795 790.010 788.885 ;
      LAYER li1 ;
        RECT 10.120 10.795 789.820 788.885 ;
      LAYER met1 ;
        RECT 2.830 10.640 789.820 795.560 ;
      LAYER met2 ;
        RECT 2.850 799.440 178.290 799.930 ;
        RECT 179.130 799.440 241.770 799.930 ;
        RECT 242.610 799.440 326.410 799.930 ;
        RECT 327.250 799.440 335.610 799.930 ;
        RECT 336.450 799.440 347.570 799.930 ;
        RECT 348.410 799.440 355.850 799.930 ;
        RECT 356.690 799.440 361.370 799.930 ;
        RECT 362.210 799.440 362.290 799.930 ;
        RECT 363.130 799.440 369.650 799.930 ;
        RECT 370.490 799.440 370.570 799.930 ;
        RECT 371.410 799.440 372.410 799.930 ;
        RECT 373.250 799.440 373.330 799.930 ;
        RECT 374.170 799.440 375.170 799.930 ;
        RECT 376.010 799.440 377.010 799.930 ;
        RECT 377.850 799.440 377.930 799.930 ;
        RECT 378.770 799.440 378.850 799.930 ;
        RECT 379.690 799.440 379.770 799.930 ;
        RECT 380.610 799.440 380.690 799.930 ;
        RECT 381.530 799.440 381.610 799.930 ;
        RECT 382.450 799.440 382.530 799.930 ;
        RECT 383.370 799.440 383.450 799.930 ;
        RECT 384.290 799.440 384.370 799.930 ;
        RECT 385.210 799.440 385.290 799.930 ;
        RECT 386.130 799.440 386.210 799.930 ;
        RECT 387.050 799.440 387.130 799.930 ;
        RECT 387.970 799.440 388.050 799.930 ;
        RECT 388.890 799.440 388.970 799.930 ;
        RECT 389.810 799.440 389.890 799.930 ;
        RECT 390.730 799.440 390.810 799.930 ;
        RECT 391.650 799.440 391.730 799.930 ;
        RECT 392.570 799.440 392.650 799.930 ;
        RECT 393.490 799.440 393.570 799.930 ;
        RECT 394.410 799.440 394.490 799.930 ;
        RECT 395.330 799.440 395.410 799.930 ;
        RECT 396.250 799.440 396.330 799.930 ;
        RECT 397.170 799.440 397.250 799.930 ;
        RECT 398.090 799.440 398.170 799.930 ;
        RECT 399.010 799.440 399.090 799.930 ;
        RECT 399.930 799.440 400.010 799.930 ;
        RECT 400.850 799.440 400.930 799.930 ;
        RECT 401.770 799.440 401.850 799.930 ;
        RECT 402.690 799.440 402.770 799.930 ;
        RECT 403.610 799.440 403.690 799.930 ;
        RECT 404.530 799.440 404.610 799.930 ;
        RECT 405.450 799.440 405.530 799.930 ;
        RECT 406.370 799.440 406.450 799.930 ;
        RECT 407.290 799.440 407.370 799.930 ;
        RECT 408.210 799.440 408.290 799.930 ;
        RECT 409.130 799.440 409.210 799.930 ;
        RECT 410.050 799.440 410.130 799.930 ;
        RECT 410.970 799.440 411.050 799.930 ;
        RECT 411.890 799.440 411.970 799.930 ;
        RECT 412.810 799.440 412.890 799.930 ;
        RECT 413.730 799.440 413.810 799.930 ;
        RECT 414.650 799.440 414.730 799.930 ;
        RECT 415.570 799.440 415.650 799.930 ;
        RECT 416.490 799.440 416.570 799.930 ;
        RECT 417.410 799.440 417.490 799.930 ;
        RECT 418.330 799.440 418.410 799.930 ;
        RECT 419.250 799.440 419.330 799.930 ;
        RECT 420.170 799.440 420.250 799.930 ;
        RECT 421.090 799.440 421.170 799.930 ;
        RECT 422.010 799.440 424.850 799.930 ;
        RECT 425.690 799.440 426.690 799.930 ;
        RECT 427.530 799.440 427.610 799.930 ;
        RECT 428.450 799.440 428.530 799.930 ;
        RECT 429.370 799.440 430.370 799.930 ;
        RECT 431.210 799.440 431.290 799.930 ;
        RECT 432.130 799.440 433.130 799.930 ;
        RECT 433.970 799.440 434.050 799.930 ;
        RECT 434.890 799.440 434.970 799.930 ;
        RECT 435.810 799.440 438.650 799.930 ;
        RECT 439.490 799.440 439.570 799.930 ;
        RECT 440.410 799.440 448.770 799.930 ;
        RECT 449.610 799.440 449.690 799.930 ;
        RECT 450.530 799.440 451.530 799.930 ;
        RECT 452.370 799.440 456.130 799.930 ;
        RECT 456.970 799.440 460.730 799.930 ;
        RECT 461.570 799.440 462.570 799.930 ;
        RECT 463.410 799.440 469.930 799.930 ;
        RECT 470.770 799.440 470.850 799.930 ;
        RECT 471.690 799.440 479.130 799.930 ;
        RECT 479.970 799.440 480.050 799.930 ;
        RECT 480.890 799.440 787.890 799.930 ;
        RECT 2.850 0.560 787.890 799.440 ;
        RECT 2.850 0.070 333.770 0.560 ;
        RECT 334.610 0.070 342.050 0.560 ;
        RECT 342.890 0.070 342.970 0.560 ;
        RECT 343.810 0.070 349.410 0.560 ;
        RECT 350.250 0.070 350.330 0.560 ;
        RECT 351.170 0.070 357.690 0.560 ;
        RECT 358.530 0.070 365.970 0.560 ;
        RECT 366.810 0.070 369.650 0.560 ;
        RECT 370.490 0.070 374.250 0.560 ;
        RECT 375.090 0.070 380.690 0.560 ;
        RECT 381.530 0.070 383.450 0.560 ;
        RECT 384.290 0.070 384.370 0.560 ;
        RECT 385.210 0.070 385.290 0.560 ;
        RECT 386.130 0.070 391.730 0.560 ;
        RECT 392.570 0.070 395.410 0.560 ;
        RECT 396.250 0.070 398.170 0.560 ;
        RECT 399.010 0.070 400.930 0.560 ;
        RECT 401.770 0.070 402.770 0.560 ;
        RECT 403.610 0.070 409.210 0.560 ;
        RECT 410.050 0.070 410.130 0.560 ;
        RECT 410.970 0.070 411.970 0.560 ;
        RECT 412.810 0.070 412.890 0.560 ;
        RECT 413.730 0.070 413.810 0.560 ;
        RECT 414.650 0.070 422.090 0.560 ;
        RECT 422.930 0.070 423.010 0.560 ;
        RECT 423.850 0.070 429.450 0.560 ;
        RECT 430.290 0.070 432.210 0.560 ;
        RECT 433.050 0.070 435.890 0.560 ;
        RECT 436.730 0.070 437.730 0.560 ;
        RECT 438.570 0.070 439.570 0.560 ;
        RECT 440.410 0.070 443.250 0.560 ;
        RECT 444.090 0.070 446.930 0.560 ;
        RECT 447.770 0.070 447.850 0.560 ;
        RECT 448.690 0.070 451.530 0.560 ;
        RECT 452.370 0.070 453.370 0.560 ;
        RECT 454.210 0.070 454.290 0.560 ;
        RECT 455.130 0.070 460.730 0.560 ;
        RECT 461.570 0.070 474.530 0.560 ;
        RECT 475.370 0.070 787.890 0.560 ;
      LAYER met3 ;
        RECT 0.600 663.360 799.400 788.965 ;
        RECT 1.000 661.960 799.400 663.360 ;
        RECT 0.600 526.000 799.400 661.960 ;
        RECT 1.000 524.600 799.400 526.000 ;
        RECT 0.600 519.200 799.400 524.600 ;
        RECT 1.000 517.800 799.400 519.200 ;
        RECT 0.600 516.480 799.400 517.800 ;
        RECT 1.000 515.080 799.400 516.480 ;
        RECT 0.600 513.760 799.400 515.080 ;
        RECT 1.000 511.000 799.400 513.760 ;
        RECT 0.600 505.600 799.400 511.000 ;
        RECT 1.000 504.200 799.400 505.600 ;
        RECT 0.600 489.280 799.400 504.200 ;
        RECT 1.000 487.880 799.400 489.280 ;
        RECT 0.600 485.200 799.400 487.880 ;
        RECT 1.000 483.800 799.400 485.200 ;
        RECT 0.600 481.120 799.400 483.800 ;
        RECT 1.000 479.720 799.400 481.120 ;
        RECT 0.600 462.080 799.400 479.720 ;
        RECT 1.000 460.680 799.400 462.080 ;
        RECT 0.600 456.640 799.400 460.680 ;
        RECT 1.000 455.240 799.400 456.640 ;
        RECT 0.600 449.840 799.400 455.240 ;
        RECT 1.000 448.440 799.400 449.840 ;
        RECT 0.600 444.400 799.400 448.440 ;
        RECT 1.000 443.000 799.400 444.400 ;
        RECT 0.600 441.680 799.400 443.000 ;
        RECT 0.600 440.280 799.000 441.680 ;
        RECT 0.600 430.800 799.400 440.280 ;
        RECT 0.600 426.680 799.000 430.800 ;
        RECT 0.600 425.360 799.400 426.680 ;
        RECT 1.000 423.960 799.400 425.360 ;
        RECT 0.600 421.280 799.400 423.960 ;
        RECT 1.000 419.880 799.400 421.280 ;
        RECT 0.600 417.200 799.400 419.880 ;
        RECT 0.600 415.800 799.000 417.200 ;
        RECT 0.600 413.120 799.400 415.800 ;
        RECT 1.000 410.360 799.400 413.120 ;
        RECT 0.600 407.680 799.400 410.360 ;
        RECT 1.000 406.280 799.000 407.680 ;
        RECT 0.600 404.920 799.000 406.280 ;
        RECT 0.600 400.880 799.400 404.920 ;
        RECT 1.000 399.520 799.400 400.880 ;
        RECT 1.000 398.120 799.000 399.520 ;
        RECT 0.600 395.440 799.400 398.120 ;
        RECT 1.000 392.720 799.400 395.440 ;
        RECT 1.000 392.680 799.000 392.720 ;
        RECT 0.600 391.320 799.000 392.680 ;
        RECT 0.600 390.000 799.400 391.320 ;
        RECT 1.000 387.240 799.400 390.000 ;
        RECT 0.600 383.200 799.400 387.240 ;
        RECT 1.000 381.800 799.400 383.200 ;
        RECT 0.600 380.480 799.400 381.800 ;
        RECT 1.000 379.120 799.400 380.480 ;
        RECT 1.000 379.080 799.000 379.120 ;
        RECT 0.600 377.760 799.000 379.080 ;
        RECT 1.000 377.720 799.000 377.760 ;
        RECT 1.000 375.000 799.400 377.720 ;
        RECT 0.600 370.960 799.400 375.000 ;
        RECT 1.000 368.200 799.400 370.960 ;
        RECT 0.600 361.440 799.400 368.200 ;
        RECT 1.000 360.040 799.400 361.440 ;
        RECT 0.600 353.280 799.400 360.040 ;
        RECT 1.000 351.880 799.400 353.280 ;
        RECT 0.600 308.400 799.400 351.880 ;
        RECT 1.000 307.000 799.400 308.400 ;
        RECT 0.600 10.715 799.400 307.000 ;
      LAYER met4 ;
        RECT 33.910 41.910 178.840 768.225 ;
        RECT 181.240 41.910 182.140 768.225 ;
        RECT 184.540 41.910 332.440 768.225 ;
        RECT 334.840 41.910 335.740 768.225 ;
        RECT 338.140 41.910 486.040 768.225 ;
        RECT 488.440 41.910 489.340 768.225 ;
        RECT 491.740 41.910 584.825 768.225 ;
      LAYER met5 ;
        RECT 33.700 492.770 580.860 573.700 ;
        RECT 33.700 339.590 580.860 484.670 ;
        RECT 33.700 186.410 580.860 331.490 ;
        RECT 33.700 41.700 580.860 178.310 ;
  END
END mul48_kernel
END LIBRARY

